VERSION 5.7 ;
  NOWIREEXTENSIONATPIN ON ;
  DIVIDERCHAR "/" ;
  BUSBITCHARS "[]" ;
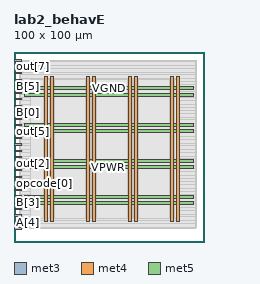
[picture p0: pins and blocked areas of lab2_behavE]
MACRO lab2_behavE
  CLASS BLOCK ;
  FOREIGN lab2_behavE ;
  ORIGIN 0.000 0.000 ;
  SIZE 100.000 BY 100.000 ;
  PIN A[0]
    DIRECTION INPUT ;
    USE SIGNAL ;
    ANTENNAGATEAREA 0.196500 ;
    PORT
      LAYER met3 ;
        RECT 0.000 95.240 4.000 95.840 ;
    END
  END A[0]
  PIN A[1]
    DIRECTION INPUT ;
    USE SIGNAL ;
    ANTENNAGATEAREA 0.213000 ;
    PORT
      LAYER met3 ;
        RECT 0.000 27.240 4.000 27.840 ;
    END
  END A[1]
  PIN A[2]
    DIRECTION INPUT ;
    USE SIGNAL ;
    ANTENNAGATEAREA 0.159000 ;
    PORT
      LAYER met3 ;
        RECT 0.000 54.440 4.000 55.040 ;
    END
  END A[2]
  PIN A[3]
    DIRECTION INPUT ;
    USE SIGNAL ;
    ANTENNAGATEAREA 0.159000 ;
    PORT
      LAYER met3 ;
        RECT 0.000 47.640 4.000 48.240 ;
    END
  END A[3]
  PIN A[4]
    DIRECTION INPUT ;
    USE SIGNAL ;
    ANTENNAGATEAREA 0.159000 ;
    PORT
      LAYER met3 ;
        RECT 0.000 13.640 4.000 14.240 ;
    END
  END A[4]
  PIN A[5]
    DIRECTION INPUT ;
    USE SIGNAL ;
    ANTENNAGATEAREA 0.159000 ;
    PORT
      LAYER met3 ;
        RECT 0.000 61.240 4.000 61.840 ;
    END
  END A[5]
  PIN A[6]
    DIRECTION INPUT ;
    USE SIGNAL ;
    ANTENNAGATEAREA 0.159000 ;
    PORT
      LAYER met3 ;
        RECT 0.000 23.840 4.000 24.440 ;
    END
  END A[6]
  PIN A[7]
    DIRECTION INPUT ;
    USE SIGNAL ;
    ANTENNAGATEAREA 0.213000 ;
    PORT
      LAYER met3 ;
        RECT 0.000 44.240 4.000 44.840 ;
    END
  END A[7]
  PIN B[0]
    DIRECTION INPUT ;
    USE SIGNAL ;
    ANTENNAGATEAREA 0.213000 ;
    PORT
      LAYER met3 ;
        RECT 0.000 68.040 4.000 68.640 ;
    END
  END B[0]
  PIN B[1]
    DIRECTION INPUT ;
    USE SIGNAL ;
    ANTENNAGATEAREA 0.213000 ;
    PORT
      LAYER met3 ;
        RECT 0.000 71.440 4.000 72.040 ;
    END
  END B[1]
  PIN B[2]
    DIRECTION INPUT ;
    USE SIGNAL ;
    ANTENNAGATEAREA 0.213000 ;
    PORT
      LAYER met3 ;
        RECT 0.000 6.840 4.000 7.440 ;
    END
  END B[2]
  PIN B[3]
    DIRECTION INPUT ;
    USE SIGNAL ;
    ANTENNAGATEAREA 0.213000 ;
    PORT
      LAYER met3 ;
        RECT 0.000 20.440 4.000 21.040 ;
    END
  END B[3]
  PIN B[4]
    DIRECTION INPUT ;
    USE SIGNAL ;
    ANTENNAGATEAREA 0.213000 ;
    PORT
      LAYER met3 ;
        RECT 0.000 78.240 4.000 78.840 ;
    END
  END B[4]
  PIN B[5]
    DIRECTION INPUT ;
    USE SIGNAL ;
    ANTENNAGATEAREA 0.159000 ;
    PORT
      LAYER met3 ;
        RECT 0.000 81.640 4.000 82.240 ;
    END
  END B[5]
  PIN B[6]
    DIRECTION INPUT ;
    USE SIGNAL ;
    ANTENNAGATEAREA 0.159000 ;
    PORT
      LAYER met3 ;
        RECT 0.000 85.040 4.000 85.640 ;
    END
  END B[6]
  PIN B[7]
    DIRECTION INPUT ;
    USE SIGNAL ;
    ANTENNAGATEAREA 0.126000 ;
    PORT
      LAYER met3 ;
        RECT 0.000 37.440 4.000 38.040 ;
    END
  END B[7]
  PIN VGND
    DIRECTION INOUT ;
    USE GROUND ;
    PORT
      LAYER met4 ;
        RECT 19.115 10.640 20.715 87.280 ;
    END
    PORT
      LAYER met4 ;
        RECT 41.310 10.640 42.910 87.280 ;
    END
    PORT
      LAYER met4 ;
        RECT 63.505 10.640 65.105 87.280 ;
    END
    PORT
      LAYER met4 ;
        RECT 85.700 10.640 87.300 87.280 ;
    END
    PORT
      LAYER met5 ;
        RECT 5.280 22.900 94.540 24.500 ;
    END
    PORT
      LAYER met5 ;
        RECT 5.280 41.940 94.540 43.540 ;
    END
    PORT
      LAYER met5 ;
        RECT 5.280 60.980 94.540 62.580 ;
    END
    PORT
      LAYER met5 ;
        RECT 5.280 80.020 94.540 81.620 ;
    END
  END VGND
  PIN VPWR
    DIRECTION INOUT ;
    USE POWER ;
    PORT
      LAYER met4 ;
        RECT 15.815 10.640 17.415 87.280 ;
    END
    PORT
      LAYER met4 ;
        RECT 38.010 10.640 39.610 87.280 ;
    END
    PORT
      LAYER met4 ;
        RECT 60.205 10.640 61.805 87.280 ;
    END
    PORT
      LAYER met4 ;
        RECT 82.400 10.640 84.000 87.280 ;
    END
    PORT
      LAYER met5 ;
        RECT 5.280 19.600 94.540 21.200 ;
    END
    PORT
      LAYER met5 ;
        RECT 5.280 38.640 94.540 40.240 ;
    END
    PORT
      LAYER met5 ;
        RECT 5.280 57.680 94.540 59.280 ;
    END
    PORT
      LAYER met5 ;
        RECT 5.280 76.720 94.540 78.320 ;
    END
  END VPWR
  PIN opcode[0]
    DIRECTION INPUT ;
    USE SIGNAL ;
    ANTENNAGATEAREA 0.213000 ;
    PORT
      LAYER met3 ;
        RECT 0.000 30.640 4.000 31.240 ;
    END
  END opcode[0]
  PIN opcode[1]
    DIRECTION INPUT ;
    USE SIGNAL ;
    ANTENNAGATEAREA 0.159000 ;
    PORT
      LAYER met3 ;
        RECT 0.000 88.440 4.000 89.040 ;
    END
  END opcode[1]
  PIN opcode[2]
    DIRECTION INPUT ;
    USE SIGNAL ;
    ANTENNAGATEAREA 0.213000 ;
    PORT
      LAYER met3 ;
        RECT 0.000 51.040 4.000 51.640 ;
    END
  END opcode[2]
  PIN out[0]
    DIRECTION OUTPUT ;
    USE SIGNAL ;
    ANTENNADIFFAREA 0.445500 ;
    PORT
      LAYER met3 ;
        RECT 0.000 34.040 4.000 34.640 ;
    END
  END out[0]
  PIN out[1]
    DIRECTION OUTPUT ;
    USE SIGNAL ;
    ANTENNADIFFAREA 0.445500 ;
    PORT
      LAYER met3 ;
        RECT 0.000 17.040 4.000 17.640 ;
    END
  END out[1]
  PIN out[2]
    DIRECTION OUTPUT ;
    USE SIGNAL ;
    ANTENNADIFFAREA 0.445500 ;
    PORT
      LAYER met3 ;
        RECT 0.000 40.840 4.000 41.440 ;
    END
  END out[2]
  PIN out[3]
    DIRECTION OUTPUT ;
    USE SIGNAL ;
    ANTENNADIFFAREA 0.445500 ;
    PORT
      LAYER met3 ;
        RECT 0.000 74.840 4.000 75.440 ;
    END
  END out[3]
  PIN out[4]
    DIRECTION OUTPUT ;
    USE SIGNAL ;
    ANTENNADIFFAREA 0.445500 ;
    PORT
      LAYER met3 ;
        RECT 0.000 10.240 4.000 10.840 ;
    END
  END out[4]
  PIN out[5]
    DIRECTION OUTPUT ;
    USE SIGNAL ;
    ANTENNADIFFAREA 0.445500 ;
    PORT
      LAYER met3 ;
        RECT 0.000 57.840 4.000 58.440 ;
    END
  END out[5]
  PIN out[6]
    DIRECTION OUTPUT ;
    USE SIGNAL ;
    ANTENNADIFFAREA 0.445500 ;
    PORT
      LAYER met3 ;
        RECT 0.000 64.640 4.000 65.240 ;
    END
  END out[6]
  PIN out[7]
    DIRECTION OUTPUT ;
    USE SIGNAL ;
    ANTENNADIFFAREA 0.445500 ;
    PORT
      LAYER met3 ;
        RECT 0.000 91.840 4.000 92.440 ;
    END
  END out[7]
  OBS
      LAYER nwell ;
        RECT 5.330 10.795 94.490 87.125 ;
      LAYER li1 ;
        RECT 5.520 10.795 94.300 87.125 ;
      LAYER met1 ;
        RECT 2.830 8.880 96.070 87.680 ;
      LAYER met2 ;
        RECT 2.860 7.635 96.040 95.725 ;
      LAYER met3 ;
        RECT 4.400 94.840 95.615 95.705 ;
        RECT 3.285 92.840 95.615 94.840 ;
        RECT 4.400 91.440 95.615 92.840 ;
        RECT 3.285 89.440 95.615 91.440 ;
        RECT 4.400 88.040 95.615 89.440 ;
        RECT 3.285 86.040 95.615 88.040 ;
        RECT 4.400 84.640 95.615 86.040 ;
        RECT 3.285 82.640 95.615 84.640 ;
        RECT 4.400 81.240 95.615 82.640 ;
        RECT 3.285 79.240 95.615 81.240 ;
        RECT 4.400 77.840 95.615 79.240 ;
        RECT 3.285 75.840 95.615 77.840 ;
        RECT 4.400 74.440 95.615 75.840 ;
        RECT 3.285 72.440 95.615 74.440 ;
        RECT 4.400 71.040 95.615 72.440 ;
        RECT 3.285 69.040 95.615 71.040 ;
        RECT 4.400 67.640 95.615 69.040 ;
        RECT 3.285 65.640 95.615 67.640 ;
        RECT 4.400 64.240 95.615 65.640 ;
        RECT 3.285 62.240 95.615 64.240 ;
        RECT 4.400 60.840 95.615 62.240 ;
        RECT 3.285 58.840 95.615 60.840 ;
        RECT 4.400 57.440 95.615 58.840 ;
        RECT 3.285 55.440 95.615 57.440 ;
        RECT 4.400 54.040 95.615 55.440 ;
        RECT 3.285 52.040 95.615 54.040 ;
        RECT 4.400 50.640 95.615 52.040 ;
        RECT 3.285 48.640 95.615 50.640 ;
        RECT 4.400 47.240 95.615 48.640 ;
        RECT 3.285 45.240 95.615 47.240 ;
        RECT 4.400 43.840 95.615 45.240 ;
        RECT 3.285 41.840 95.615 43.840 ;
        RECT 4.400 40.440 95.615 41.840 ;
        RECT 3.285 38.440 95.615 40.440 ;
        RECT 4.400 37.040 95.615 38.440 ;
        RECT 3.285 35.040 95.615 37.040 ;
        RECT 4.400 33.640 95.615 35.040 ;
        RECT 3.285 31.640 95.615 33.640 ;
        RECT 4.400 30.240 95.615 31.640 ;
        RECT 3.285 28.240 95.615 30.240 ;
        RECT 4.400 26.840 95.615 28.240 ;
        RECT 3.285 24.840 95.615 26.840 ;
        RECT 4.400 23.440 95.615 24.840 ;
        RECT 3.285 21.440 95.615 23.440 ;
        RECT 4.400 20.040 95.615 21.440 ;
        RECT 3.285 18.040 95.615 20.040 ;
        RECT 4.400 16.640 95.615 18.040 ;
        RECT 3.285 14.640 95.615 16.640 ;
        RECT 4.400 13.240 95.615 14.640 ;
        RECT 3.285 11.240 95.615 13.240 ;
        RECT 4.400 9.840 95.615 11.240 ;
        RECT 3.285 7.840 95.615 9.840 ;
        RECT 4.400 6.990 95.615 7.840 ;
      LAYER met4 ;
        RECT 8.575 12.415 15.415 85.505 ;
        RECT 17.815 12.415 18.715 85.505 ;
        RECT 21.115 12.415 37.610 85.505 ;
        RECT 40.010 12.415 40.910 85.505 ;
        RECT 43.310 12.415 59.805 85.505 ;
        RECT 62.205 12.415 63.105 85.505 ;
        RECT 65.505 12.415 82.000 85.505 ;
        RECT 84.400 12.415 85.265 85.505 ;
  END
END lab2_behavE
END LIBRARY

